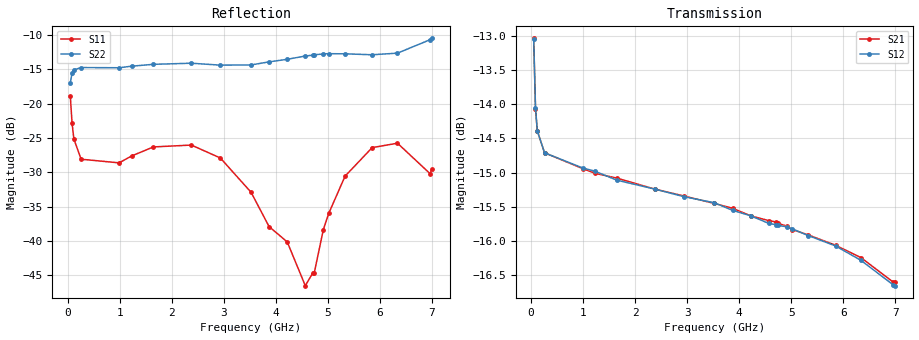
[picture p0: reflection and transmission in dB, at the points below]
! Integrated Device Technology
! Corporate Headquarters
! 6024 Silver Creek Valley Road
! San Jose, CA 95138  USA
! Phone:  1-408-284-8200
! Toll Free:  1-800-223-1366
! Webpage:  http://www.idt.com/
! Timing and RF Division
! 515 Groton Road, Suite 102
! Westford, MA 01886-6024
! Device:  F2258
! Description: Voltage Variable RF Attenuator
! Frequency:  50.0 -  6000.00 MHz
! Package:  3x3 mm Thin QFN Plastic Package: 16 pin
! Ports:  2 RF, 2 DC
!  Pin  1  = NC
!  Pin  2  = NC
!  Pin  3  = RF2  = Port 2
!  Pin  4  = GND
!  Pin  5  = Vdd
!  Pin  6  = NC
!  Pin  7  = VCTRL
!  Pin  8  = NC
!  Pin  9  = GND
!  Pin 10  = RF1  = Port 1
!  Pin 11  = NC
!  Pin 12  = NC
!  Pin 13  = NC
!  Pin 14  = NC
!  Pin 15  = NC
!  Pin 16  = NC
! Vcntrl:  1.170 Volts
! Vdd:  +3.300 Volts
! Current:  1.165 mA
! Data:  The device was measured on a the F2258 evaluation board which has
!  individual transmission lines to the RF pins.  Data was collected
!  using a calibrated network analyzer.  The evaluation board was
!  de-embedded using a TRL calibration technique.
!  The reference plane is the edge of the package pin.
! Misc:  SN 10
!  Action Tracker AT0285
! Date Measured:  2014-12-10
! Date:  2016-01-13  MJV
! Note:
!  Integrated Device Technology supplies this data as a sample of measured
!  data at the package pin for this product.  Your particular data for this
!  product may vary.
!  Data was taken at 25 degrees C.
!  Integrated Device Technology reserves the right to change this data at anytime.
!Freq_(GHz)  S11M_(dB)  S11P_(deg)  S21M_(dB)  S21P_(deg)  S12M_(dB)  S12P_(deg)  S22M_(dB)  S22P_(deg)
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# GHz S dB R 50
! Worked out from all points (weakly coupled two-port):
!   201 points, 50 MHz to 7 GHz, reference 50 ohm
!   highest |S21| = -13.04 dB at 50 MHz (marker M1); lowest = -16.6 dB at 6.965 GHz (marker M2)
!   lowest |S11| = -46.5 dB at 4.567 GHz (marker M3), VSWR 1.01, Z = 50.2 + j0.407 ohm
!   |S11| at or under -10 dB: start of sweep to end of sweep
!   |S22| runs from -17.0 to -10.5 dB; largest |S21 - S12| = 0.0014
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0.05  -18.85 -91.7  -13.04 -22.4  -13.05 -22.4  -17.00 -22.3
0.08475  -22.86 -75.5  -14.07 -16.0  -14.05 -16.0  -15.51 -12.2
0.1195  -25.16 -62.5  -14.39 -12.8  -14.39 -12.8  -15.08 -10.0
0.2585  -28.09 -34.7  -14.71 -9.6  -14.71 -9.6  -14.74 -10.2
0.98825  -28.62 -18.9  -14.94 -17.1  -14.93 -17.1  -14.77 -28.8
1.2315  -27.61 -15.7  -15.01 -20.6  -14.98 -20.6  -14.54 -34.9
1.6485  -26.30 -12.1  -15.08 -26.6  -15.11 -26.6  -14.27 -44.9
2.37825  -26.03 -2.1  -15.24 -37.1  -15.24 -37.1  -14.11 -62.3
2.93425  -27.91 9.1  -15.34 -45.4  -15.35 -45.4  -14.39 -78.3
3.525  -32.90 28.3  -15.45 -54.3  -15.44 -54.3  -14.36 -100.2
3.8725  -37.92 51.8  -15.52 -59.5  -15.55 -59.5  -13.91 -113.1
4.22  -40.13 77.3  -15.63 -64.7  -15.63 -64.7  -13.54 -123.3
4.5675  -46.51 59.1  -15.70 -69.8  -15.74 -69.7  -13.06 -131.3
4.7065  -44.72 12.9  -15.72 -71.8  -15.76 -71.7  -12.94 -133.6
4.74125  -44.59 4.9  -15.74 -72.3  -15.77 -72.3  -12.89 -134.2
4.915  -38.33 -17.1  -15.78 -74.8  -15.79 -74.8  -12.75 -136.8
5.01925  -35.96 -17.3  -15.83 -76.2  -15.82 -76.3  -12.72 -138.5
5.332  -30.56 -18.4  -15.91 -80.7  -15.92 -80.6  -12.74 -142.4
5.85325  -26.40 -9.0  -16.06 -88.0  -16.07 -88.0  -12.88 -151.7
6.33975  -25.76 5.1  -16.24 -95.0  -16.28 -95.0  -12.64 -163.8
6.96525  -30.19 81.8  -16.60 -103.0  -16.64 -102.9  -10.69 178.6
7  -29.56 90.8  -16.60 -103.4  -16.65 -103.3  -10.49 177.6
